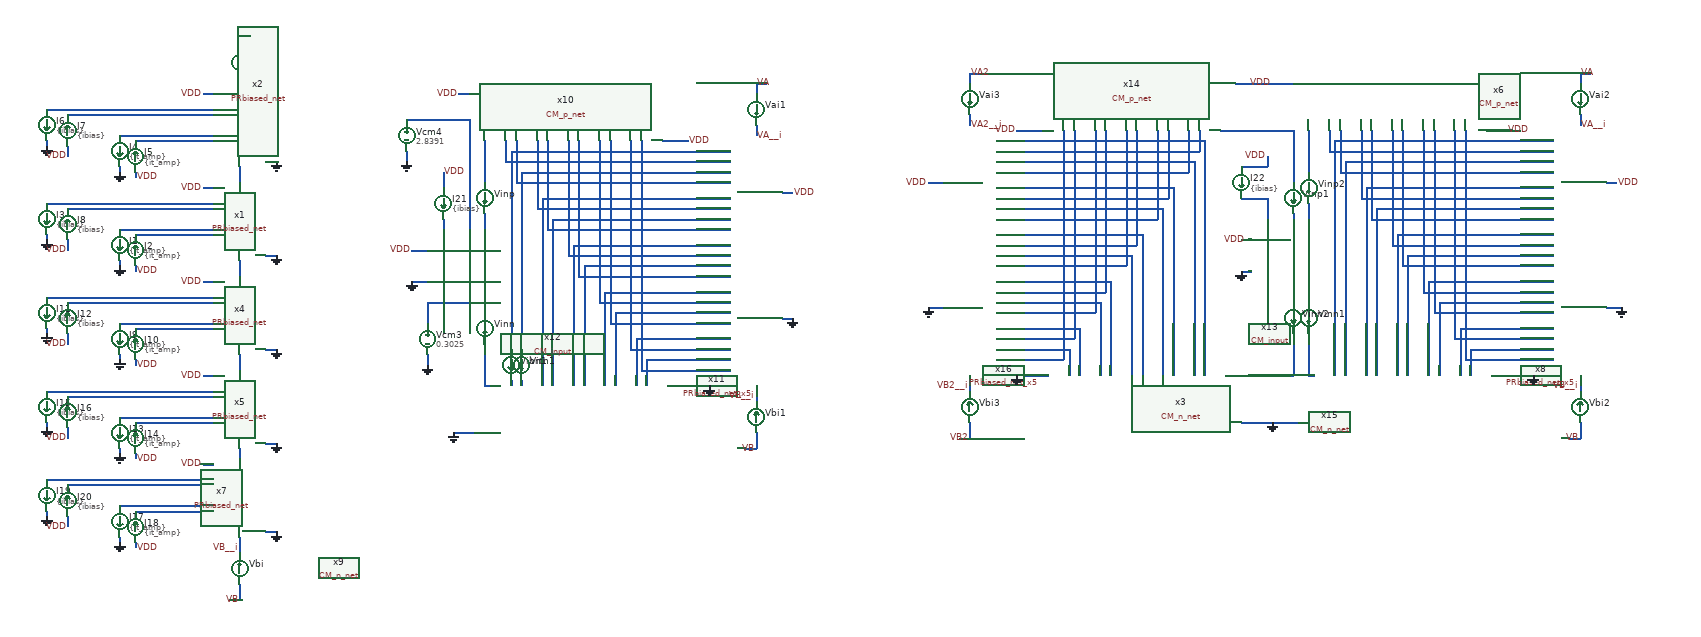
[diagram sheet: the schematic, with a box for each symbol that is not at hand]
v {xschem version=3.4.5 file_version=1.2
}
G {}
K {}
V {}
S {}
E {}
N 600 -720 620 -720 {
lab=VA}
N 600 -720 600 -700 {
lab=VA}
N 600 -640 600 -620 {
lab=VA__i}
N 600 -470 600 -440 {
lab=#net1}
N 370 -530 550 -530 {
lab=#net2}
N 400 -520 550 -520 {
lab=#net3}
N 230 -580 550 -580 {
lab=#net4}
N 270 -570 550 -570 {
lab=#net5}
N 370 -470 370 -460 {
lab=GND}
N 230 -520 230 -510 {
lab=GND}
N 270 -510 270 -490 {
lab=VDD}
N 400 -460 400 -450 {
lab=VDD}
N 530 -610 550 -610 {
lab=VDD}
N 650 -480 670 -480 {
lab=GND}
N 600 -290 600 -260 {
lab=#net6}
N 370 -350 550 -350 {
lab=#net7}
N 400 -340 550 -340 {
lab=#net8}
N 230 -400 550 -400 {
lab=#net9}
N 270 -390 550 -390 {
lab=#net10}
N 370 -290 370 -280 {
lab=GND}
N 230 -340 230 -330 {
lab=GND}
N 270 -330 270 -310 {
lab=VDD}
N 400 -280 400 -270 {
lab=VDD}
N 530 -430 550 -430 {
lab=VDD}
N 650 -300 670 -300 {
lab=GND}
N 600 -110 600 -80 {
lab=#net11}
N 370 -170 550 -170 {
lab=#net12}
N 400 -160 550 -160 {
lab=#net13}
N 230 -220 550 -220 {
lab=#net14}
N 270 -210 550 -210 {
lab=#net15}
N 370 -110 370 -100 {
lab=GND}
N 230 -160 230 -150 {
lab=GND}
N 270 -150 270 -130 {
lab=VDD}
N 400 -100 400 -90 {
lab=VDD}
N 530 -250 550 -250 {
lab=VDD}
N 650 -120 670 -120 {
lab=GND}
N 370 10 550 10 {
lab=#net16}
N 400 20 550 20 {
lab=#net17}
N 230 -40 550 -40 {
lab=#net18}
N 270 -30 550 -30 {
lab=#net19}
N 370 70 370 80 {
lab=GND}
N 230 20 230 30 {
lab=GND}
N 270 30 270 50 {
lab=VDD}
N 400 80 400 90 {
lab=VDD}
N 530 -70 550 -70 {
lab=VDD}
N 650 60 670 60 {
lab=GND}
N 370 180 550 180 {
lab=#net20}
N 400 190 550 190 {
lab=#net21}
N 230 130 550 130 {
lab=#net22}
N 270 140 550 140 {
lab=#net23}
N 370 240 370 250 {
lab=GND}
N 230 190 230 200 {
lab=GND}
N 270 200 270 220 {
lab=VDD}
N 400 250 400 260 {
lab=VDD}
N 530 100 550 100 {
lab=VDD}
N 650 230 670 230 {
lab=GND}
N 580 360 600 360 {
lab=VB}
N 600 240 600 270 {
lab=VB__i}
N 600 330 600 360 {
lab=VB}
N 600 70 600 90 {
lab=#net24}
N 990 -370 990 -350 {
lab=#net25}
N 990 -460 990 -430 {
lab=VDD}
N 930 -310 960 -310 {
lab=VDD}
N 1010 40 1040 40 {
lab=GND}
N 930 -250 960 -250 {
lab=GND}
N 1020 -610 1040 -610 {
lab=VDD}
N 1590 -630 1610 -630 {
lab=VA}
N 1590 -630 1590 -610 {
lab=VA}
N 1590 -550 1590 -530 {
lab=VA__i}
N 1570 70 1590 70 {
lab=VB}
N 1590 -50 1590 -20 {
lab=VB__i}
N 1590 40 1590 70 {
lab=VB}
N 1640 -180 1660 -180 {
lab=GND}
N 1640 -420 1660 -420 {
lab=VDD}
N 1070 -210 1070 -190 {
lab=#net26}
N 1070 -130 1070 -50 {
lab=#net27}
N 1070 -380 1070 -350 {
lab=#net28}
N 1070 -520 1070 -440 {
lab=#net29}
N 1070 -50 1080 -50 {
lab=#net27}
N 1120 -500 1540 -500 {
lab=#net30}
N 1140 -460 1540 -460 {
lab=#net31}
N 1180 -410 1540 -410 {
lab=#net32}
N 1180 -410 1180 -50 {
lab=#net32}
N 1240 -320 1540 -320 {
lab=#net33}
N 1240 -320 1240 -50 {
lab=#net33}
N 1260 -280 1260 -50 {
lab=#net34}
N 1260 -280 1540 -280 {
lab=#net34}
N 1300 -230 1540 -230 {
lab=#net35}
N 1300 -230 1300 -50 {
lab=#net35}
N 1320 -190 1540 -190 {
lab=#net36}
N 1320 -190 1320 -50 {
lab=#net36}
N 1360 -140 1360 -50 {
lab=#net37}
N 1360 -140 1540 -140 {
lab=#net37}
N 1380 -100 1540 -100 {
lab=#net38}
N 1380 -100 1380 -50 {
lab=#net38}
N 1200 -370 1540 -370 {
lab=#net39}
N 1200 -370 1200 -340 {
lab=#net39}
N 1200 -340 1200 -50 {
lab=#net39}
N 1110 -480 1540 -480 {
lab=#net40}
N 1110 -520 1110 -480 {
lab=#net40}
N 1130 -440 1540 -440 {
lab=#net41}
N 1130 -520 1130 -440 {
lab=#net41}
N 1170 -390 1540 -390 {
lab=#net42}
N 1170 -520 1170 -390 {
lab=#net42}
N 1190 -350 1540 -350 {
lab=#net43}
N 1190 -520 1190 -350 {
lab=#net43}
N 1230 -300 1540 -300 {
lab=#net44}
N 1230 -520 1230 -300 {
lab=#net44}
N 1250 -260 1540 -260 {
lab=#net45}
N 1250 -520 1250 -260 {
lab=#net45}
N 1290 -210 1540 -210 {
lab=#net46}
N 1290 -520 1290 -210 {
lab=#net46}
N 1310 -170 1540 -170 {
lab=#net47}
N 1310 -520 1310 -170 {
lab=#net47}
N 1350 -120 1540 -120 {
lab=#net48}
N 1350 -520 1350 -120 {
lab=#net48}
N 1370 -80 1540 -80 {
lab=#net49}
N 1370 -520 1370 -80 {
lab=#net49}
N 960 -110 960 -90 {
lab=GND}
N 960 -210 960 -170 {
lab=#net50}
N 960 -210 1040 -210 {
lab=#net50}
N 920 -560 1030 -560 {
lab=#net51}
N 1030 -560 1040 -560 {
lab=#net51}
N 1040 -560 1040 -350 {
lab=#net51}
N 920 -500 920 -480 {
lab=GND}
N 1040 40 1050 40 {
lab=GND}
N 1120 -500 1120 -120 {
lab=#net30}
N 1120 -60 1120 -50 {
lab=#net52}
N 1140 -460 1140 -120 {
lab=#net31}
N 1140 -60 1140 -50 {
lab=#net53}
N 1420 -50 1500 -50 {
lab=GND}
N 1410 -520 1460 -520 {
lab=VDD}
N 2650 -230 2650 -210 {
lab=#net3}
N 2650 -150 2650 -70 {
lab=#net4}
N 2650 -400 2650 -370 {
lab=#net5}
N 2650 -540 2650 -460 {
lab=#net6}
N 2650 -70 2660 -70 {
lab=#net4}
N 2700 -520 3120 -520 {
lab=#net7}
N 2720 -480 3120 -480 {
lab=#net8}
N 2760 -430 3120 -430 {
lab=#net9}
N 2760 -430 2760 -70 {
lab=#net9}
N 2820 -340 3120 -340 {
lab=#net10}
N 2820 -340 2820 -70 {
lab=#net10}
N 2840 -300 2840 -70 {
lab=#net11}
N 2840 -300 3120 -300 {
lab=#net11}
N 2880 -250 3120 -250 {
lab=#net12}
N 2880 -250 2880 -70 {
lab=#net12}
N 2900 -210 3120 -210 {
lab=#net13}
N 2900 -210 2900 -70 {
lab=#net13}
N 2940 -160 2940 -70 {
lab=#net14}
N 2940 -160 3120 -160 {
lab=#net14}
N 2960 -120 3120 -120 {
lab=#net15}
N 2960 -120 2960 -70 {
lab=#net15}
N 2780 -390 3120 -390 {
lab=#net16}
N 2780 -360 2780 -70 {
lab=#net16}
N 2690 -500 3120 -500 {
lab=#net17}
N 2690 -540 2690 -500 {
lab=#net17}
N 2710 -460 3120 -460 {
lab=#net18}
N 2710 -540 2710 -460 {
lab=#net18}
N 2750 -410 3120 -410 {
lab=#net19}
N 2750 -540 2750 -410 {
lab=#net19}
N 2770 -370 3120 -370 {
lab=#net20}
N 2770 -540 2770 -370 {
lab=#net20}
N 2810 -320 3120 -320 {
lab=#net21}
N 2810 -540 2810 -320 {
lab=#net21}
N 2830 -280 3120 -280 {
lab=#net22}
N 2830 -540 2830 -280 {
lab=#net22}
N 2870 -230 3120 -230 {
lab=#net23}
N 2870 -540 2870 -230 {
lab=#net23}
N 2890 -190 3120 -190 {
lab=#net24}
N 2890 -540 2890 -190 {
lab=#net24}
N 2930 -140 3120 -140 {
lab=#net25}
N 2930 -540 2930 -140 {
lab=#net25}
N 2950 -100 3120 -100 {
lab=#net26}
N 2950 -540 2950 -100 {
lab=#net26}
N 2700 -520 2700 -140 {
lab=#net7}
N 2720 -480 2720 -140 {
lab=#net8}
N 3000 -70 3080 -70 {
lab=GND}
N 2990 -540 3040 -540 {
lab=VDD}
N 2780 -390 2780 -360 {
lab=#net16}
N 2700 -140 2700 -70 {
lab=#net7}
N 2720 -140 2720 -70 {
lab=#net8}
N 2480 -540 2620 -540 {
lab=#net27}
N 2490 -70 2620 -70 {
lab=#net28}
N 2520 20 2630 20 {
lab=GND}
N 2510 -630 2620 -630 {
lab=VDD}
N 2090 -70 2150 -70 {
lab=GND}
N 2050 -520 2440 -520 {
lab=#net29}
N 2440 -520 2450 -520 {
lab=#net29}
N 2450 -520 2450 -70 {
lab=#net29}
N 2430 -480 2430 -70 {
lab=#net30}
N 2050 -480 2430 -480 {
lab=#net30}
N 2050 -430 2390 -430 {
lab=#net31}
N 2390 -430 2390 -70 {
lab=#net31}
N 2370 -390 2370 -70 {
lab=#net32}
N 2050 -390 2370 -390 {
lab=#net32}
N 2050 -340 2330 -340 {
lab=#net33}
N 2330 -340 2330 -70 {
lab=#net33}
N 2310 -300 2310 -70 {
lab=#net34}
N 2050 -300 2310 -300 {
lab=#net34}
N 2050 -250 2270 -250 {
lab=#net35}
N 2270 -250 2270 -70 {
lab=#net35}
N 2250 -210 2250 -70 {
lab=#net36}
N 2050 -210 2250 -210 {
lab=#net36}
N 2050 -160 2210 -160 {
lab=#net37}
N 2210 -160 2210 -70 {
lab=#net37}
N 2190 -120 2190 -70 {
lab=#net38}
N 2050 -120 2190 -120 {
lab=#net38}
N 2440 -540 2440 -500 {
lab=#net29}
N 2050 -500 2440 -500 {
lab=#net29}
N 2050 -460 2420 -460 {
lab=#net39}
N 2420 -540 2420 -460 {
lab=#net39}
N 2050 -410 2380 -410 {
lab=#net40}
N 2380 -540 2380 -410 {
lab=#net40}
N 2050 -370 2360 -370 {
lab=#net41}
N 2360 -540 2360 -370 {
lab=#net41}
N 2050 -320 2320 -320 {
lab=#net42}
N 2320 -540 2320 -320 {
lab=#net42}
N 2300 -540 2300 -280 {
lab=#net43}
N 2050 -280 2300 -280 {
lab=#net43}
N 2260 -540 2260 -230 {
lab=#net44}
N 2050 -230 2260 -230 {
lab=#net44}
N 2240 -540 2240 -190 {
lab=#net45}
N 2050 -190 2240 -190 {
lab=#net45}
N 2200 -540 2200 -140 {
lab=#net46}
N 2050 -140 2200 -140 {
lab=#net46}
N 2180 -540 2180 -100 {
lab=#net47}
N 2050 -100 2180 -100 {
lab=#net47}
N 2570 -410 2570 -370 {
lab=#net48}
N 2520 -330 2540 -330 {
lab=VDD}
N 2520 -270 2540 -270 {
lab=GND}
N 2090 -540 2140 -540 {
lab=VDD}
N 3220 -440 3240 -440 {
lab=VDD}
N 1920 -440 1950 -440 {
lab=VDD}
N 1920 -200 1950 -200 {
lab=GND}
N 3220 -200 3250 -200 {
lab=GND}
N 2570 -490 2570 -470 {
lab=VDD}
N 2620 -540 2620 -440 {
lab=#net27}
N 2620 -380 2620 -370 {
lab=#net49}
N 2520 -410 2570 -410 {
lab=#net48}
N 2520 -470 2570 -470 {
lab=VDD}
N 2620 -230 2620 -210 {
lab=#net50}
N 2620 -150 2620 -70 {
lab=#net28}
N 3170 -650 3190 -650 {
lab=VA}
N 3170 -650 3170 -630 {
lab=VA}
N 3170 -570 3170 -550 {
lab=VA__i}
N 3150 50 3170 50 {
lab=VB}
N 3170 -70 3170 -40 {
lab=VB__i}
N 3170 20 3170 50 {
lab=VB}
N 1980 50 2000 50 {
lab=VB2}
N 2000 -70 2000 -40 {
lab=VB2__i}
N 2000 20 2000 50 {
lab=VB2}
N 2000 -650 2020 -650 {
lab=VA2}
N 2000 -650 2000 -630 {
lab=VA2}
N 2000 -570 2000 -550 {
lab=VA2__i}
C {devices/lab_wire.sym} 600 -720 0 1 {name=p12 sig_type=std_logic lab=VA
}
C {devices/lab_wire.sym} 600 -620 0 1 {name=p14 sig_type=std_logic lab=VA__i
}
C {devices/ammeter.sym} 600 -670 0 0 {name=Vai
}
C {devices/isource.sym} 370 -500 0 1 {name=I4 value=\{it_amp\}}
C {devices/isource.sym} 400 -490 2 1 {name=I5 value=\{it_amp\}}
C {devices/isource.sym} 230 -550 0 1 {name=I6 value=\{ibias\}}
C {devices/isource.sym} 270 -540 2 1 {name=I7 value=\{ibias\}}
C {devices/gnd.sym} 230 -510 0 1 {name=l4 lab=GND}
C {devices/gnd.sym} 370 -460 0 1 {name=l5 lab=GND}
C {devices/lab_wire.sym} 270 -490 2 1 {name=p28 sig_type=std_logic lab=VDD}
C {devices/lab_wire.sym} 400 -450 2 0 {name=p29 sig_type=std_logic lab=VDD}
C {devices/lab_wire.sym} 530 -610 0 0 {name=p30 sig_type=std_logic lab=VDD}
C {devices/gnd.sym} 670 -480 0 0 {name=l8 lab=GND}
C {PRbiased_net.sym} 520 -370 0 0 {name=x1}
C {devices/isource.sym} 370 -320 0 1 {name=I1 value=\{it_amp\}}
C {devices/isource.sym} 400 -310 2 1 {name=I2 value=\{it_amp\}}
C {devices/isource.sym} 230 -370 0 1 {name=I3 value=\{ibias\}}
C {devices/isource.sym} 270 -360 2 1 {name=I8 value=\{ibias\}}
C {devices/gnd.sym} 230 -330 0 1 {name=l1 lab=GND}
C {devices/gnd.sym} 370 -280 0 1 {name=l2 lab=GND}
C {devices/lab_wire.sym} 270 -310 2 1 {name=p5 sig_type=std_logic lab=VDD}
C {devices/lab_wire.sym} 400 -270 2 0 {name=p6 sig_type=std_logic lab=VDD}
C {devices/lab_wire.sym} 530 -430 0 0 {name=p7 sig_type=std_logic lab=VDD}
C {devices/gnd.sym} 670 -300 0 0 {name=l3 lab=GND}
C {PRbiased_net.sym} 520 -190 0 0 {name=x4}
C {devices/isource.sym} 370 -140 0 1 {name=I9 value=\{it_amp\}}
C {devices/isource.sym} 400 -130 2 1 {name=I10 value=\{it_amp\}}
C {devices/isource.sym} 230 -190 0 1 {name=I11 value=\{ibias\}}
C {devices/isource.sym} 270 -180 2 1 {name=I12 value=\{ibias\}}
C {devices/gnd.sym} 230 -150 0 1 {name=l6 lab=GND}
C {devices/gnd.sym} 370 -100 0 1 {name=l7 lab=GND}
C {devices/lab_wire.sym} 270 -130 2 1 {name=p16 sig_type=std_logic lab=VDD}
C {devices/lab_wire.sym} 400 -90 2 0 {name=p17 sig_type=std_logic lab=VDD}
C {devices/lab_wire.sym} 530 -250 0 0 {name=p25 sig_type=std_logic lab=VDD}
C {devices/gnd.sym} 670 -120 0 0 {name=l15 lab=GND}
C {PRbiased_net.sym} 520 -10 0 0 {name=x5}
C {devices/isource.sym} 370 40 0 1 {name=I13 value=\{it_amp\}}
C {devices/isource.sym} 400 50 2 1 {name=I14 value=\{it_amp\}}
C {devices/isource.sym} 230 -10 0 1 {name=I15 value=\{ibias\}}
C {devices/isource.sym} 270 0 2 1 {name=I16 value=\{ibias\}}
C {devices/gnd.sym} 230 30 0 1 {name=l16 lab=GND}
C {devices/gnd.sym} 370 80 0 1 {name=l17 lab=GND}
C {devices/lab_wire.sym} 270 50 2 1 {name=p33 sig_type=std_logic lab=VDD}
C {devices/lab_wire.sym} 400 90 2 0 {name=p34 sig_type=std_logic lab=VDD}
C {devices/lab_wire.sym} 530 -70 0 0 {name=p35 sig_type=std_logic lab=VDD}
C {devices/gnd.sym} 670 60 0 0 {name=l18 lab=GND}
C {PRbiased_net.sym} 520 160 0 0 {name=x7}
C {devices/isource.sym} 370 210 0 1 {name=I17 value=\{it_amp\}}
C {devices/isource.sym} 400 220 2 1 {name=I18 value=\{it_amp\}}
C {devices/isource.sym} 230 160 0 1 {name=I19 value=\{ibias\}}
C {devices/isource.sym} 270 170 2 1 {name=I20 value=\{ibias\}}
C {devices/gnd.sym} 230 200 0 1 {name=l19 lab=GND}
C {devices/gnd.sym} 370 250 0 1 {name=l20 lab=GND}
C {devices/lab_wire.sym} 270 220 2 1 {name=p40 sig_type=std_logic lab=VDD}
C {devices/lab_wire.sym} 400 260 2 0 {name=p41 sig_type=std_logic lab=VDD}
C {devices/lab_wire.sym} 530 100 0 0 {name=p42 sig_type=std_logic lab=VDD}
C {devices/gnd.sym} 670 230 0 0 {name=l21 lab=GND}
C {devices/lab_wire.sym} 600 360 0 0 {name=p58 sig_type=std_logic lab=VB
}
C {devices/lab_wire.sym} 600 260 0 0 {name=p59 sig_type=std_logic lab=VB__i
}
C {devices/ammeter.sym} 600 300 2 0 {name=Vbi
}
C {PseudoResistor/PRbiased_net.sym} 520 -550 0 0 {name=x2}
C {CurrentMirrors/CM_n_net.sym} 790 300 0 0 {name=x9}
C {CurrentMirrors/CM_p_net.sym} 1280 -480 0 0 {name=x10}
C {PseudoResistor/PRbiased_net_x5.sym} 1550 -300 1 0 {name=x11}
C {CurrentMirrors/CM_input.sym} 1060 -290 0 0 {name=x12}
C {devices/isource.sym} 990 -400 0 1 {name=I21 value=\{ibias\}}
C {devices/lab_wire.sym} 930 -310 0 0 {name=p1 sig_type=std_logic lab=VDD}
C {devices/lab_wire.sym} 990 -460 0 1 {name=p2 sig_type=std_logic lab=VDD}
C {devices/gnd.sym} 1010 40 0 1 {name=l22 lab=GND}
C {devices/gnd.sym} 930 -250 0 1 {name=l23 lab=GND}
C {devices/lab_wire.sym} 1020 -610 0 0 {name=p3 sig_type=std_logic lab=VDD}
C {devices/lab_wire.sym} 1590 -630 0 1 {name=p4 sig_type=std_logic lab=VA
}
C {devices/lab_wire.sym} 1590 -530 0 1 {name=p8 sig_type=std_logic lab=VA__i
}
C {devices/ammeter.sym} 1590 -580 0 0 {name=Vai1
}
C {devices/lab_wire.sym} 1590 70 0 0 {name=p9 sig_type=std_logic lab=VB
}
C {devices/lab_wire.sym} 1590 -30 0 0 {name=p10 sig_type=std_logic lab=VB__i
}
C {devices/ammeter.sym} 1590 10 2 1 {name=Vbi1}
C {devices/gnd.sym} 1660 -180 0 0 {name=l24 lab=GND}
C {devices/lab_wire.sym} 1660 -420 0 1 {name=p11 sig_type=std_logic lab=VDD}
C {devices/ammeter.sym} 1070 -160 0 0 {name=Vinn
}
C {devices/ammeter.sym} 1070 -410 0 0 {name=Vinp
}
C {devices/vsource.sym} 960 -140 0 0 {name=Vcm3 value=0.3025}
C {devices/gnd.sym} 960 -90 0 0 {name=l9 lab=GND}
C {devices/vsource.sym} 920 -530 0 0 {name=Vcm4 value=2.8391}
C {devices/gnd.sym} 920 -480 0 0 {name=l10 lab=GND}
C {devices/ammeter.sym} 1120 -90 0 1 {name=Vibn1
}
C {devices/ammeter.sym} 1140 -90 0 0 {name=Vitn1
}
C {devices/gnd.sym} 1500 -50 0 0 {name=l11 lab=GND}
C {devices/lab_wire.sym} 1460 -520 0 1 {name=p13 sig_type=std_logic lab=VDD}
C {CurrentMirrors/CM_n_net.sym} 2370 280 0 0 {name=x3}
C {CurrentMirrors/CM_p_net.sym} 2860 -500 0 0 {name=x6}
C {PseudoResistor/PRbiased_net_x5.sym} 3130 -320 1 0 {name=x8}
C {CurrentMirrors/CM_input.sym} 2640 -310 0 0 {name=x13}
C {CurrentMirrors/CM_p_net.sym} 2270 -500 0 1 {name=x14}
C {CurrentMirrors/CM_n_net.sym} 2780 280 0 1 {name=x15}
C {PseudoResistor/PRbiased_net_x5.sym} 2040 -320 3 1 {name=x16}
C {devices/lab_wire.sym} 2580 -630 0 0 {name=p15 sig_type=std_logic lab=VDD}
C {devices/lab_wire.sym} 2530 -330 0 0 {name=p18 sig_type=std_logic lab=VDD}
C {devices/lab_wire.sym} 3240 -440 0 1 {name=p19 sig_type=std_logic lab=VDD}
C {devices/lab_wire.sym} 1920 -440 0 0 {name=p20 sig_type=std_logic lab=VDD}
C {devices/lab_wire.sym} 2090 -540 0 0 {name=p21 sig_type=std_logic lab=VDD}
C {devices/isource.sym} 2520 -440 0 1 {name=I22 value=\{ibias\}}
C {devices/ammeter.sym} 2650 -180 0 0 {name=Vinn1
}
C {devices/lab_wire.sym} 2570 -490 0 0 {name=p22 sig_type=std_logic lab=VDD}
C {devices/ammeter.sym} 2620 -410 0 1 {name=Vinp1
}
C {devices/ammeter.sym} 2650 -430 0 0 {name=Vinp2
}
C {devices/ammeter.sym} 2620 -180 0 1 {name=Vinn2
}
C {devices/lab_wire.sym} 3170 -650 0 1 {name=p23 sig_type=std_logic lab=VA
}
C {devices/lab_wire.sym} 3170 -550 0 1 {name=p24 sig_type=std_logic lab=VA__i
}
C {devices/ammeter.sym} 3170 -600 0 0 {name=Vai2
}
C {devices/lab_wire.sym} 3170 50 0 0 {name=p26 sig_type=std_logic lab=VB
}
C {devices/lab_wire.sym} 3170 -50 0 0 {name=p27 sig_type=std_logic lab=VB__i
}
C {devices/ammeter.sym} 3170 -10 2 1 {name=Vbi2
}
C {devices/lab_wire.sym} 2000 50 0 0 {name=p31 sig_type=std_logic lab=VB2
}
C {devices/lab_wire.sym} 2000 -50 0 0 {name=p32 sig_type=std_logic lab=VB2__i
}
C {devices/ammeter.sym} 2000 -10 2 1 {name=Vbi3
}
C {devices/lab_wire.sym} 2000 -650 0 1 {name=p36 sig_type=std_logic lab=VA2
}
C {devices/lab_wire.sym} 2000 -550 0 1 {name=p37 sig_type=std_logic lab=VA2__i
}
C {devices/ammeter.sym} 2000 -600 0 0 {name=Vai3
}
C {devices/lab_wire.sym} 3030 -540 0 1 {name=p38 sig_type=std_logic lab=VDD}
C {devices/gnd.sym} 1920 -200 0 1 {name=l12 lab=GND}
C {devices/gnd.sym} 2090 -70 0 1 {name=l13 lab=GND}
C {devices/gnd.sym} 2580 20 0 1 {name=l14 lab=GND}
C {devices/gnd.sym} 3080 -70 0 0 {name=l25 lab=GND}
C {devices/gnd.sym} 3250 -200 0 0 {name=l26 lab=GND}
C {devices/gnd.sym} 2520 -270 0 1 {name=l27 lab=GND}
